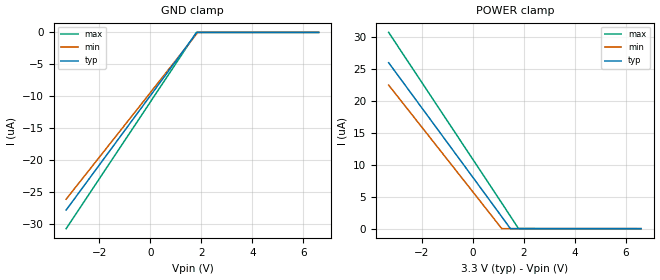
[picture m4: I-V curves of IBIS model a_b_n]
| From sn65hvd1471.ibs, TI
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[Model]   a_b_n
Model_type   Input
Vinl = 0.8
Vinh = 2
|   typ   min   max
|   (nom PVT)   (fast PVT)   (slow PVT)
|Average
C_comp   3.733e-12   3.726e-12   3.785e-12
| Where nom  PVT is Nominal Process, 3.3V, 27C
|   Fast PVT is Strong Process,  3.6V, -40C
|   Slow PVT is Weak Process,   3V, 150C
[Voltage Range]   3.3   3   3.6
|Ambient Temperature   25   125   -40
|Junction Temperature
[Temperature Range]   27   150   -40
[Power Clamp Reference]   3.3   3   3.6
[GND Clamp Reference]   0   0   0
[GND Clamp]
|   Voltage   I(typ)   I(min)   I(max)
-3.3V     -27.88uA   -26.18uA   -30.8uA
1.805V    -109.5nA   -297.7nA   -13.81nA
1.863V    0A         0A         0A
6.6V      0A         0A         0A
[POWER Clamp]
|   Voltage   I(typ)   I(min)   I(max)
-3.3V     25.99uA    22.48uA    30.73uA
1.134V    1.868uA    13.28nA    4.016uA
1.475V    0A         0A         1.94uA
1.79V     0A         0A         15.49nA
6.6V      0A         0A         0A
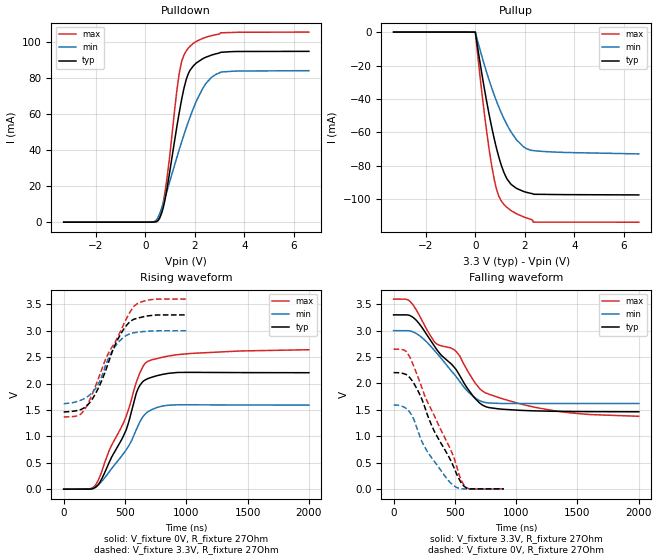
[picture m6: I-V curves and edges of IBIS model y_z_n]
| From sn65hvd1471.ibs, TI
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[Model]   y_z_n
Model_type   Output
Polarity   Non-Inverting
Vmeas = 1.65
Vref = 1.99
Cref = 50pF
Rref = 27
|   typ   min   max
|   (nom PVT)   (fast PVT)   (slow PVT)
|Average
C_comp   1.240e-11   1.223e-11   1.351e-11
| Where nom  PVT is Nominal Process, 3.3V, 27C
|   Fast PVT is Strong Process,  3.6V, -40C
|   Slow PVT is Weak Process,   3V, 150C
[Voltage Range]   3.3   3   3.6
|Ambient Temperature   25   125   -40
|Junction Temperature
[Temperature Range]   27   150   -40
[Pullup Reference]   3.3   3   3.6
[Pulldown Reference]   0   0   0
[Power Clamp Reference]   3.3   3   3.6
[GND Clamp Reference]   0   0   0
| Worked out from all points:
|   slope of the pulldown table from 0 to 0.495 V, typ, clamps not added: 593 ohm
|   slope of the pullup table from 0 to 0.495 V, typ, clamps not added: 11.2 ohm
|   falling waveform, V_fixture 3.3V, R_fixture 27Ohm: 20-80 % time 358ns typ, 292ns min, 508ns max; typ from 3.3 V to 1.46 V
|   rising waveform, V_fixture 0V, R_fixture 27Ohm: 20-80 % time 227ns typ, 253ns min, 268ns max; typ from 0 V to 2.21 V
|   rising waveform, V_fixture 3.3V, R_fixture 27Ohm: 20-80 % time 200ns typ, 170ns min, 260ns max; typ from 1.46 V to 3.3 V
|   falling waveform, V_fixture 0V, R_fixture 27Ohm: 20-80 % time 267ns typ, 223ns min, 302ns max; typ from 2.21 V to 0 V
[Pulldown]
|   Voltage   I(typ)   I(min)   I(max)
-3.3V     -6.612uA   -9.319uA   -6.374uA
327mV     34.23uA    194.1uA    14.87uA
516mV     1.082mA    2.854mA    989.7uA
663.6mV   5.354mA    8.176mA    6.979mA
855mV     17.28mA    16.66mA    22.83mA
1.373V    61.46mA    40.64mA    83.28mA
1.476V    69.14mA    45.18mA    89.88mA
1.65V     79.37mA    52.48mA    95.25mA
1.934V    86.9mA     63.21mA    99.38mA
2.439V    91.7mA     77.05mA    102.8mA
3.057V    94.46mA    83.51mA    105.3mA
6.6V      94.97mA    84.24mA    105.7mA
[Pullup]
|   Voltage   I(typ)   I(min)   I(max)
-3.3V     13.21uA    17.02uA    13.33uA
0V        0A         0A         0A
372mV     -34.36mA   -19.92mA   -49.51mA
666mV     -57.22mA   -33.57mA   -80.34mA
816mV     -67.13mA   -39.77mA   -91.61mA
948mV     -74.69mA   -44.78mA   -98.05mA
1.155V    -83.97mA   -51.77mA   -103.1mA
1.287V    -88mA      -55.68mA   -105mA
1.68V     -93.6mA    -64.71mA   -108.8mA
2.211V    -96.37mA   -70.55mA   -111.8mA
2.34V     -96.86mA   -70.88mA   -113.7mA
6.6V      -97.4mA    -72.86mA   -113.7mA
[Ramp]
R_load = 27
|   typ   min   max
dV/dt_r   1.32325/2.28004e-07   0.954968/2.52405e-07   1.58421/2.67898e-07
dV/dt_f   1.10261/3.57066e-07   0.829016/2.91114e-07   1.33396/5.07787e-07
[Falling Waveform]
V_fixture = 3.3V
V_fixture_min = 3V
V_fixture_max = 3.6V
R_fixture = 27Ohm
|   Time   V(typ)   V(min)   V(max)
0s        3.3V       3V         3.6V
117.8ns   3.297V     2.999V     3.584V
181.2ns   3.207V     2.951V     3.41V
332ns     2.711V     2.628V     2.79V
511.3ns   2.259V     2.126V     2.603V
646.5ns   1.767V     1.758V     2.074V
746.7ns   1.564V     1.639V     1.823V
1.025us   1.49V      1.619V     1.617V
1.311us   1.472V     1.619V     1.481V
2us       1.462V     1.618V     1.377V
[Rising Waveform]
V_fixture = 0V
V_fixture_min = 0V
V_fixture_max = 0V
R_fixture = 27Ohm
|   Time   V(typ)   V(min)   V(max)
0s        11.28nV    106.8nV    12.29nV
211.9ns   751.5uV    5.798mV    1.547mV
263.3ns   40.1mV     49.26mV    90.6mV
301ns     152.7mV    124.3mV    272.4mV
372.1ns   511.4mV    330.2mV    738.4mV
510.9ns   1.128V     749.1mV    1.388V
608.4ns   1.909V     1.21V      2.126V
681.3ns   2.088V     1.457V     2.414V
925.4ns   2.209V     1.597V     2.546V
2us       2.205V     1.592V     2.64V
[Rising Waveform]
V_fixture = 3.3V
V_fixture_min = 3V
V_fixture_max = 3.6V
R_fixture = 27Ohm
|   Time   V(typ)   V(min)   V(max)
0s        1.461V     1.618V     1.366V
115.5ns   1.49V      1.664V     1.39V
173.3ns   1.549V     1.72V      1.517V
278.6ns   1.894V     1.977V     2.068V
358.7ns   2.353V     2.442V     2.543V
426.2ns   2.764V     2.724V     2.812V
513.6ns   3.105V     2.914V     3.237V
574.5ns   3.219V     2.963V     3.467V
683.8ns   3.281V     2.992V     3.58V
1us       3.3V       3V         3.6V
[Falling Waveform]
V_fixture = 0V
V_fixture_min = 0V
V_fixture_max = 0V
R_fixture = 27Ohm
|   Time   V(typ)   V(min)   V(max)
0s        2.205V     1.59V      2.65V
86ns      2.184V     1.549V     2.633V
129.4ns   2.117V     1.465V     2.511V
167.8ns   1.991V     1.302V     2.307V
220.8ns   1.754V     953.6mV    1.984V
310.8ns   1.2V       588.1mV    1.489V
470.9ns   515.8mV    98.5mV     712.7mV
573.1ns   52.97mV    427.1uV    74.17mV
634.6ns   235.2uV    204uV      -5.589mV
899.5ns   7.237uV    7.174uV    7.829uV
